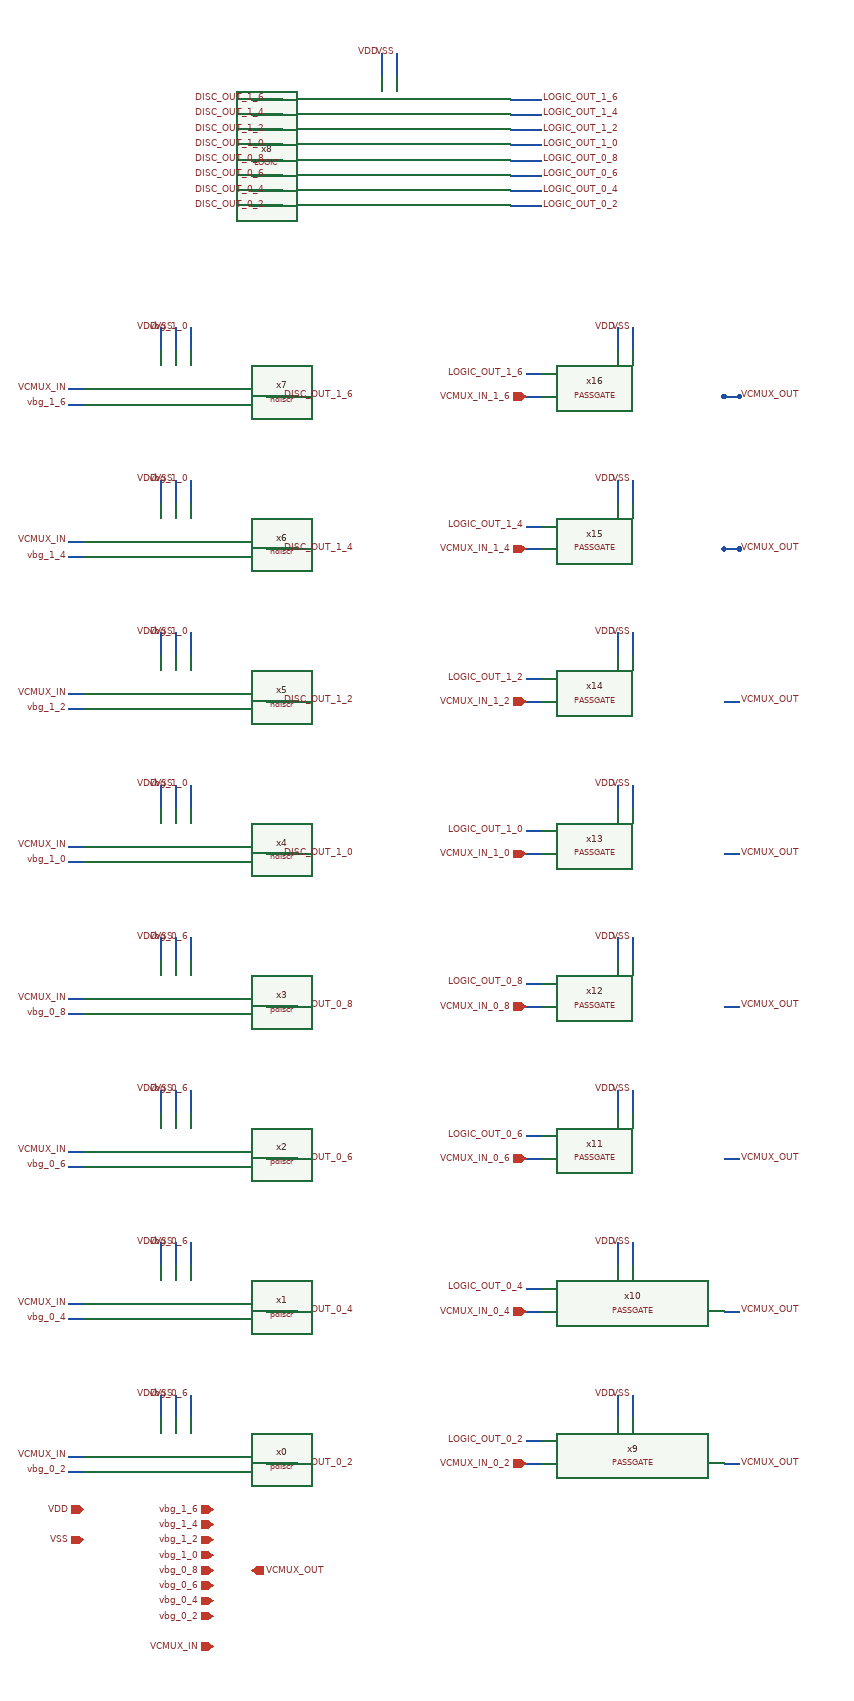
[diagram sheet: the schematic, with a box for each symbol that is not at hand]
v {xschem version=3.4.5 file_version=1.2
}
G {}
K {}
V {}
S {}
E {}
N 160 -130 160 -100 {
lab=vbg_0_6}
N 120 -130 120 -100 {
lab=VDD}
N 140 -130 140 -100 {
lab=VSS}
N 0 -50 20 -50 {
lab=VCMUX_IN}
N 0 -30 20 -30 {
lab=vbg_0_2}
N 260 -40 300 -40 {
lab=DISC_OUT_0_2}
N 160 -330 160 -300 {
lab=vbg_0_6}
N 120 -330 120 -300 {
lab=VDD}
N 140 -330 140 -300 {
lab=VSS}
N 0 -250 20 -250 {
lab=VCMUX_IN}
N 0 -230 20 -230 {
lab=vbg_0_4}
N 260 -240 300 -240 {
lab=DISC_OUT_0_4}
N 160 -530 160 -500 {
lab=vbg_0_6}
N 120 -530 120 -500 {
lab=VDD}
N 140 -530 140 -500 {
lab=VSS}
N 0 -450 20 -450 {
lab=VCMUX_IN}
N 0 -430 20 -430 {
lab=vbg_0_6}
N 260 -440 300 -440 {
lab=DISC_OUT_0_6}
N 160 -730 160 -700 {
lab=vbg_0_6}
N 120 -730 120 -700 {
lab=VDD}
N 140 -730 140 -700 {
lab=VSS}
N 0 -650 20 -650 {
lab=VCMUX_IN}
N 0 -630 20 -630 {
lab=vbg_0_8}
N 260 -640 300 -640 {
lab=DISC_OUT_0_8}
N 0 -850 20 -850 {
lab=VCMUX_IN}
N 0 -830 20 -830 {
lab=vbg_1_0}
N 160 -930 160 -900 {
lab=vbg_1_0}
N 120 -930 120 -900 {
lab=VDD}
N 140 -930 140 -900 {
lab=VSS}
N 260 -840 300 -840 {
lab=DISC_OUT_1_0}
N 0 -1050 20 -1050 {
lab=VCMUX_IN}
N 0 -1030 20 -1030 {
lab=vbg_1_2}
N 160 -1130 160 -1100 {
lab=vbg_1_0}
N 120 -1130 120 -1100 {
lab=VDD}
N 140 -1130 140 -1100 {
lab=VSS}
N 260 -1040 300 -1040 {
lab=DISC_OUT_1_2}
N 0 -1250 20 -1250 {
lab=VCMUX_IN}
N 0 -1230 20 -1230 {
lab=vbg_1_4}
N 160 -1330 160 -1300 {
lab=vbg_1_0}
N 120 -1330 120 -1300 {
lab=VDD}
N 140 -1330 140 -1300 {
lab=VSS}
N 260 -1240 300 -1240 {
lab=DISC_OUT_1_4}
N 0 -1450 20 -1450 {
lab=VCMUX_IN}
N 0 -1430 20 -1430 {
lab=vbg_1_6}
N 160 -1530 160 -1500 {
lab=vbg_1_0}
N 120 -1530 120 -1500 {
lab=VDD}
N 140 -1530 140 -1500 {
lab=VSS}
N 260 -1440 300 -1440 {
lab=DISC_OUT_1_6}
N 240 -1830 280 -1830 {
lab=DISC_OUT_1_6}
N 240 -1790 280 -1790 {
lab=DISC_OUT_1_2}
N 240 -1810 280 -1810 {
lab=DISC_OUT_1_4}
N 240 -1770 280 -1770 {
lab=DISC_OUT_1_0}
N 240 -1750 280 -1750 {
lab=DISC_OUT_0_8}
N 240 -1730 280 -1730 {
lab=DISC_OUT_0_6}
N 240 -1690 280 -1690 {
lab=DISC_OUT_0_2}
N 240 -1710 280 -1710 {
lab=DISC_OUT_0_4}
N 720 -130 720 -100 {
lab=VDD}
N 740 -130 740 -100 {
lab=VSS}
N 860 -40 880 -40 {
lab=VCMUX_OUT}
N 600 -40 620 -40 {
lab=VCMUX_IN_0_2}
N 580 -1830 620 -1830 {
lab=LOGIC_OUT_1_6}
N 580 -1790 620 -1790 {
lab=LOGIC_OUT_1_2}
N 580 -1810 620 -1810 {
lab=LOGIC_OUT_1_4}
N 580 -1770 620 -1770 {
lab=LOGIC_OUT_1_0}
N 580 -1750 620 -1750 {
lab=LOGIC_OUT_0_8}
N 580 -1730 620 -1730 {
lab=LOGIC_OUT_0_6}
N 580 -1690 620 -1690 {
lab=LOGIC_OUT_0_2}
N 580 -1710 620 -1710 {
lab=LOGIC_OUT_0_4}
N 600 -70 620 -70 {
lab=LOGIC_OUT_0_2}
N 720 -330 720 -300 {
lab=VDD}
N 740 -330 740 -300 {
lab=VSS}
N 860 -240 880 -240 {
lab=VCMUX_OUT}
N 600 -240 620 -240 {
lab=VCMUX_IN_0_4}
N 600 -270 620 -270 {
lab=LOGIC_OUT_0_4}
N 720 -530 720 -500 {
lab=VDD}
N 740 -530 740 -500 {
lab=VSS}
N 860 -440 880 -440 {
lab=VCMUX_OUT}
N 600 -440 620 -440 {
lab=VCMUX_IN_0_6}
N 600 -470 620 -470 {
lab=LOGIC_OUT_0_6}
N 720 -730 720 -700 {
lab=VDD}
N 740 -730 740 -700 {
lab=VSS}
N 860 -640 880 -640 {
lab=VCMUX_OUT}
N 600 -640 620 -640 {
lab=VCMUX_IN_0_8}
N 600 -670 620 -670 {
lab=LOGIC_OUT_0_8}
N 720 -930 720 -900 {
lab=VDD}
N 740 -930 740 -900 {
lab=VSS}
N 860 -840 880 -840 {
lab=VCMUX_OUT}
N 600 -840 620 -840 {
lab=VCMUX_IN_1_0}
N 600 -870 620 -870 {
lab=LOGIC_OUT_1_0}
N 720 -1130 720 -1100 {
lab=VDD}
N 740 -1130 740 -1100 {
lab=VSS}
N 860 -1040 880 -1040 {
lab=VCMUX_OUT}
N 600 -1040 620 -1040 {
lab=VCMUX_IN_1_2}
N 600 -1070 620 -1070 {
lab=LOGIC_OUT_1_2}
N 720 -1330 720 -1300 {
lab=VDD}
N 740 -1330 740 -1300 {
lab=VSS}
N 860 -1240 880 -1240 {
lab=VCMUX_OUT}
N 600 -1240 620 -1240 {
lab=VCMUX_IN_1_4}
N 600 -1270 620 -1270 {
lab=LOGIC_OUT_1_4}
N 720 -1530 720 -1500 {
lab=VDD}
N 740 -1530 740 -1500 {
lab=VSS}
N 860 -1440 880 -1440 {
lab=VCMUX_OUT}
N 600 -1440 620 -1440 {
lab=VCMUX_IN_1_6}
N 600 -1470 620 -1470 {
lab=LOGIC_OUT_1_6}
N 860 -440 880 -440 {
lab=VCMUX_OUT}
N 860 -640 880 -640 {
lab=VCMUX_OUT}
N 860 -840 880 -840 {
lab=VCMUX_OUT}
N 860 -1040 880 -1040 {
lab=VCMUX_OUT}
N 860 -1240 880 -1240 {
lab=VCMUX_OUT}
N 860 -1440 880 -1440 {
lab=VCMUX_OUT}
N 860 -1240 880 -1240 {
lab=VCMUX_OUT}
N 860 -1440 880 -1440 {
lab=VCMUX_OUT}
N 410 -1890 410 -1860 {
lab=VDD}
N 430 -1890 430 -1860 {
lab=VSS}
C {devices/lab_wire.sym} 120 -130 3 1 {name=p20 sig_type=std_logic lab=VDD}
C {devices/lab_wire.sym} 140 -130 3 1 {name=p26 sig_type=std_logic lab=VSS}
C {devices/lab_wire.sym} 160 -130 3 1 {name=p27 sig_type=std_logic lab=vbg_0_6}
C {devices/lab_wire.sym} 0 -50 0 0 {name=p28 sig_type=std_logic lab=VCMUX_IN}
C {devices/lab_wire.sym} 0 -30 0 0 {name=p29 sig_type=std_logic lab=vbg_0_2}
C {devices/lab_wire.sym} 280 -40 0 1 {name=p33 sig_type=std_logic lab=DISC_OUT_0_2}
C {pdiscr.sym} 20 -40 0 0 {name=x0}
C {devices/lab_wire.sym} 120 -330 3 1 {name=p1 sig_type=std_logic lab=VDD}
C {devices/lab_wire.sym} 140 -330 3 1 {name=p2 sig_type=std_logic lab=VSS}
C {devices/lab_wire.sym} 160 -330 3 1 {name=p3 sig_type=std_logic lab=vbg_0_6}
C {devices/lab_wire.sym} 0 -250 0 0 {name=p4 sig_type=std_logic lab=VCMUX_IN}
C {devices/lab_wire.sym} 0 -230 0 0 {name=p5 sig_type=std_logic lab=vbg_0_4}
C {devices/lab_wire.sym} 280 -240 0 1 {name=p6 sig_type=std_logic lab=DISC_OUT_0_4}
C {pdiscr.sym} 20 -240 0 0 {name=x1}
C {devices/lab_wire.sym} 120 -530 3 1 {name=p7 sig_type=std_logic lab=VDD}
C {devices/lab_wire.sym} 140 -530 3 1 {name=p8 sig_type=std_logic lab=VSS}
C {devices/lab_wire.sym} 160 -530 3 1 {name=p9 sig_type=std_logic lab=vbg_0_6}
C {devices/lab_wire.sym} 0 -450 0 0 {name=p10 sig_type=std_logic lab=VCMUX_IN}
C {devices/lab_wire.sym} 0 -430 0 0 {name=p11 sig_type=std_logic lab=vbg_0_6}
C {devices/lab_wire.sym} 280 -440 0 1 {name=p12 sig_type=std_logic lab=DISC_OUT_0_6}
C {pdiscr.sym} 20 -440 0 0 {name=x2}
C {devices/lab_wire.sym} 120 -730 3 1 {name=p13 sig_type=std_logic lab=VDD}
C {devices/lab_wire.sym} 140 -730 3 1 {name=p14 sig_type=std_logic lab=VSS}
C {devices/lab_wire.sym} 160 -730 3 1 {name=p15 sig_type=std_logic lab=vbg_0_6}
C {devices/lab_wire.sym} 0 -650 0 0 {name=p16 sig_type=std_logic lab=VCMUX_IN}
C {devices/lab_wire.sym} 0 -630 0 0 {name=p17 sig_type=std_logic lab=vbg_0_8}
C {devices/lab_wire.sym} 280 -640 0 1 {name=p18 sig_type=std_logic lab=DISC_OUT_0_8}
C {pdiscr.sym} 20 -640 0 0 {name=x3}
C {ndiscr.sym} 20 -840 0 0 {name=x4}
C {devices/lab_wire.sym} 0 -850 0 0 {name=p19 sig_type=std_logic lab=VCMUX_IN}
C {devices/lab_wire.sym} 0 -830 0 0 {name=p21 sig_type=std_logic lab=vbg_1_0}
C {devices/lab_wire.sym} 120 -930 3 1 {name=p22 sig_type=std_logic lab=VDD}
C {devices/lab_wire.sym} 140 -930 3 1 {name=p23 sig_type=std_logic lab=VSS}
C {devices/lab_wire.sym} 160 -930 3 1 {name=p24 sig_type=std_logic lab=vbg_1_0}
C {devices/lab_wire.sym} 280 -840 0 1 {name=p25 sig_type=std_logic lab=DISC_OUT_1_0}
C {ndiscr.sym} 20 -1040 0 0 {name=x5}
C {devices/lab_wire.sym} 0 -1050 0 0 {name=p30 sig_type=std_logic lab=VCMUX_IN}
C {devices/lab_wire.sym} 0 -1030 0 0 {name=p31 sig_type=std_logic lab=vbg_1_2}
C {devices/lab_wire.sym} 120 -1130 3 1 {name=p32 sig_type=std_logic lab=VDD}
C {devices/lab_wire.sym} 140 -1130 3 1 {name=p34 sig_type=std_logic lab=VSS}
C {devices/lab_wire.sym} 160 -1130 3 1 {name=p35 sig_type=std_logic lab=vbg_1_0}
C {devices/lab_wire.sym} 280 -1040 0 1 {name=p36 sig_type=std_logic lab=DISC_OUT_1_2}
C {ndiscr.sym} 20 -1240 0 0 {name=x6}
C {devices/lab_wire.sym} 0 -1250 0 0 {name=p37 sig_type=std_logic lab=VCMUX_IN}
C {devices/lab_wire.sym} 0 -1230 0 0 {name=p38 sig_type=std_logic lab=vbg_1_4}
C {devices/lab_wire.sym} 120 -1330 3 1 {name=p39 sig_type=std_logic lab=VDD}
C {devices/lab_wire.sym} 140 -1330 3 1 {name=p40 sig_type=std_logic lab=VSS}
C {devices/lab_wire.sym} 160 -1330 3 1 {name=p41 sig_type=std_logic lab=vbg_1_0}
C {devices/lab_wire.sym} 280 -1240 0 1 {name=p42 sig_type=std_logic lab=DISC_OUT_1_4}
C {ndiscr.sym} 20 -1440 0 0 {name=x7}
C {devices/lab_wire.sym} 0 -1450 0 0 {name=p43 sig_type=std_logic lab=VCMUX_IN}
C {devices/lab_wire.sym} 0 -1430 0 0 {name=p44 sig_type=std_logic lab=vbg_1_6}
C {devices/lab_wire.sym} 120 -1530 3 1 {name=p45 sig_type=std_logic lab=VDD}
C {devices/lab_wire.sym} 140 -1530 3 1 {name=p46 sig_type=std_logic lab=VSS}
C {devices/lab_wire.sym} 160 -1530 3 1 {name=p47 sig_type=std_logic lab=vbg_1_0}
C {devices/lab_wire.sym} 280 -1440 0 1 {name=p48 sig_type=std_logic lab=DISC_OUT_1_6}
C {devices/iopin.sym} 20 20 0 0 {name=p49 lab=VDD}
C {devices/iopin.sym} 20 60 0 0 {name=p50 lab=VSS}
C {devices/ipin.sym} 190 20 0 0 {name=p67 lab=vbg_1_6}
C {devices/ipin.sym} 190 40 0 0 {name=p68 lab=vbg_1_4}
C {devices/ipin.sym} 190 60 0 0 {name=p69 lab=vbg_1_2}
C {devices/ipin.sym} 190 80 0 0 {name=p70 lab=vbg_1_0}
C {devices/ipin.sym} 190 100 0 0 {name=p71 lab=vbg_0_8}
C {devices/ipin.sym} 190 120 0 0 {name=p72 lab=vbg_0_6}
C {devices/ipin.sym} 190 140 0 0 {name=p73 lab=vbg_0_4}
C {devices/ipin.sym} 190 160 0 0 {name=p74 lab=vbg_0_2}
C {devices/ipin.sym} 190 200 0 0 {name=p75 lab=VCMUX_IN}
C {LOGIC.sym} 430 -1760 0 0 {name=x8}
C {PASSGATE.sym} 780 -40 0 0 {name=x9}
C {devices/lab_wire.sym} 260 -1830 0 0 {name=p76 sig_type=std_logic lab=DISC_OUT_1_6}
C {devices/lab_wire.sym} 260 -1790 0 0 {name=p77 sig_type=std_logic lab=DISC_OUT_1_2}
C {devices/lab_wire.sym} 260 -1810 0 0 {name=p78 sig_type=std_logic lab=DISC_OUT_1_4}
C {devices/lab_wire.sym} 260 -1770 0 0 {name=p79 sig_type=std_logic lab=DISC_OUT_1_0}
C {devices/lab_wire.sym} 260 -1750 0 0 {name=p80 sig_type=std_logic lab=DISC_OUT_0_8}
C {devices/lab_wire.sym} 260 -1730 0 0 {name=p81 sig_type=std_logic lab=DISC_OUT_0_6}
C {devices/lab_wire.sym} 260 -1690 0 0 {name=p82 sig_type=std_logic lab=DISC_OUT_0_2}
C {devices/lab_wire.sym} 260 -1710 0 0 {name=p83 sig_type=std_logic lab=DISC_OUT_0_4}
C {devices/lab_wire.sym} 720 -130 3 1 {name=p84 sig_type=std_logic lab=VDD}
C {devices/lab_wire.sym} 740 -130 3 1 {name=p85 sig_type=std_logic lab=VSS}
C {devices/ipin.sym} 600 -40 0 0 {name=p87 lab=VCMUX_IN_0_2}
C {devices/lab_wire.sym} 620 -1830 0 1 {name=p88 sig_type=std_logic lab=LOGIC_OUT_1_6}
C {devices/lab_wire.sym} 620 -1790 0 1 {name=p89 sig_type=std_logic lab=LOGIC_OUT_1_2}
C {devices/lab_wire.sym} 620 -1810 0 1 {name=p90 sig_type=std_logic lab=LOGIC_OUT_1_4}
C {devices/lab_wire.sym} 620 -1770 0 1 {name=p91 sig_type=std_logic lab=LOGIC_OUT_1_0}
C {devices/lab_wire.sym} 620 -1750 0 1 {name=p92 sig_type=std_logic lab=LOGIC_OUT_0_8}
C {devices/lab_wire.sym} 620 -1730 0 1 {name=p93 sig_type=std_logic lab=LOGIC_OUT_0_6}
C {devices/lab_wire.sym} 620 -1690 0 1 {name=p94 sig_type=std_logic lab=LOGIC_OUT_0_2}
C {devices/lab_wire.sym} 620 -1710 0 1 {name=p95 sig_type=std_logic lab=LOGIC_OUT_0_4}
C {PASSGATE.sym} 780 -240 0 0 {name=x10}
C {devices/lab_wire.sym} 720 -330 3 1 {name=p96 sig_type=std_logic lab=VDD}
C {devices/lab_wire.sym} 740 -330 3 1 {name=p97 sig_type=std_logic lab=VSS}
C {devices/ipin.sym} 600 -240 0 0 {name=p99 lab=VCMUX_IN_0_4}
C {PASSGATE.sym} 780 -440 0 0 {name=x11}
C {devices/lab_wire.sym} 720 -530 3 1 {name=p100 sig_type=std_logic lab=VDD}
C {devices/lab_wire.sym} 740 -530 3 1 {name=p101 sig_type=std_logic lab=VSS}
C {devices/ipin.sym} 600 -440 0 0 {name=p103 lab=VCMUX_IN_0_6}
C {PASSGATE.sym} 780 -640 0 0 {name=x12}
C {devices/lab_wire.sym} 720 -730 3 1 {name=p104 sig_type=std_logic lab=VDD}
C {devices/lab_wire.sym} 740 -730 3 1 {name=p105 sig_type=std_logic lab=VSS}
C {devices/ipin.sym} 600 -640 0 0 {name=p107 lab=VCMUX_IN_0_8}
C {PASSGATE.sym} 780 -840 0 0 {name=x13}
C {devices/lab_wire.sym} 720 -930 3 1 {name=p108 sig_type=std_logic lab=VDD}
C {devices/lab_wire.sym} 740 -930 3 1 {name=p109 sig_type=std_logic lab=VSS}
C {devices/ipin.sym} 600 -840 0 0 {name=p111 lab=VCMUX_IN_1_0}
C {PASSGATE.sym} 780 -1040 0 0 {name=x14}
C {devices/lab_wire.sym} 720 -1130 3 1 {name=p112 sig_type=std_logic lab=VDD}
C {devices/lab_wire.sym} 740 -1130 3 1 {name=p113 sig_type=std_logic lab=VSS}
C {devices/ipin.sym} 600 -1040 0 0 {name=p115 lab=VCMUX_IN_1_2}
C {PASSGATE.sym} 780 -1240 0 0 {name=x15}
C {devices/lab_wire.sym} 720 -1330 3 1 {name=p116 sig_type=std_logic lab=VDD}
C {devices/lab_wire.sym} 740 -1330 3 1 {name=p117 sig_type=std_logic lab=VSS}
C {devices/opin.sym} 240 100 0 0 {name=p118 sig_type=std_logic lab=VCMUX_OUT}
C {devices/ipin.sym} 600 -1240 0 0 {name=p119 lab=VCMUX_IN_1_4}
C {PASSGATE.sym} 780 -1440 0 0 {name=x16}
C {devices/lab_wire.sym} 720 -1530 3 1 {name=p120 sig_type=std_logic lab=VDD}
C {devices/lab_wire.sym} 740 -1530 3 1 {name=p121 sig_type=std_logic lab=VSS}
C {devices/ipin.sym} 600 -1440 0 0 {name=p123 lab=VCMUX_IN_1_6}
C {devices/lab_wire.sym} 600 -70 0 0 {name=p51 sig_type=std_logic lab=LOGIC_OUT_0_2}
C {devices/lab_wire.sym} 600 -1470 0 0 {name=p52 sig_type=std_logic lab=LOGIC_OUT_1_6}
C {devices/lab_wire.sym} 600 -1270 0 0 {name=p53 sig_type=std_logic lab=LOGIC_OUT_1_4}
C {devices/lab_wire.sym} 600 -1070 0 0 {name=p54 sig_type=std_logic lab=LOGIC_OUT_1_2}
C {devices/lab_wire.sym} 600 -870 0 0 {name=p55 sig_type=std_logic lab=LOGIC_OUT_1_0}
C {devices/lab_wire.sym} 600 -670 0 0 {name=p56 sig_type=std_logic lab=LOGIC_OUT_0_8}
C {devices/lab_wire.sym} 600 -470 0 0 {name=p57 sig_type=std_logic lab=LOGIC_OUT_0_6}
C {devices/lab_wire.sym} 600 -270 0 0 {name=p58 sig_type=std_logic lab=LOGIC_OUT_0_4}
C {devices/lab_wire.sym} 880 -40 0 1 {name=p59 sig_type=std_logic lab=VCMUX_OUT}
C {devices/lab_wire.sym} 880 -240 0 1 {name=p60 sig_type=std_logic lab=VCMUX_OUT}
C {devices/lab_wire.sym} 880 -440 0 1 {name=p61 sig_type=std_logic lab=VCMUX_OUT}
C {devices/lab_wire.sym} 880 -640 0 1 {name=p62 sig_type=std_logic lab=VCMUX_OUT}
C {devices/lab_wire.sym} 880 -840 0 1 {name=p63 sig_type=std_logic lab=VCMUX_OUT}
C {devices/lab_wire.sym} 880 -1040 0 1 {name=p64 sig_type=std_logic lab=VCMUX_OUT}
C {devices/lab_wire.sym} 880 -1240 0 1 {name=p65 sig_type=std_logic lab=VCMUX_OUT}
C {devices/lab_wire.sym} 880 -1440 0 1 {name=p66 sig_type=std_logic lab=VCMUX_OUT}
C {devices/lab_wire.sym} 410 -1890 3 1 {name=p86 sig_type=std_logic lab=VDD}
C {devices/lab_wire.sym} 430 -1890 3 1 {name=p98 sig_type=std_logic lab=VSS}
